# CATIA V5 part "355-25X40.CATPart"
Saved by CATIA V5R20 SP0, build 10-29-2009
Part number: 355-25X40
Definition: NONE
Nomenclature: 355-25X40
Source: Unknown
Description: 355-25X40
Bounding box of the stored display mesh (mm): x -23 to 17, y -19 to 19, z -19 to 19
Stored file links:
  C:\Users\Utente\Desktop\IO LAVORO\3D X SITO CF\X SITO\PLASTICA\355\355-25X40.CATPart

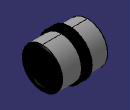
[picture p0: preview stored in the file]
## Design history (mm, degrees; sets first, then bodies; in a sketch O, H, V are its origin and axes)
Body1 "355-25X40" (main body)
  Solid1: solid without history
